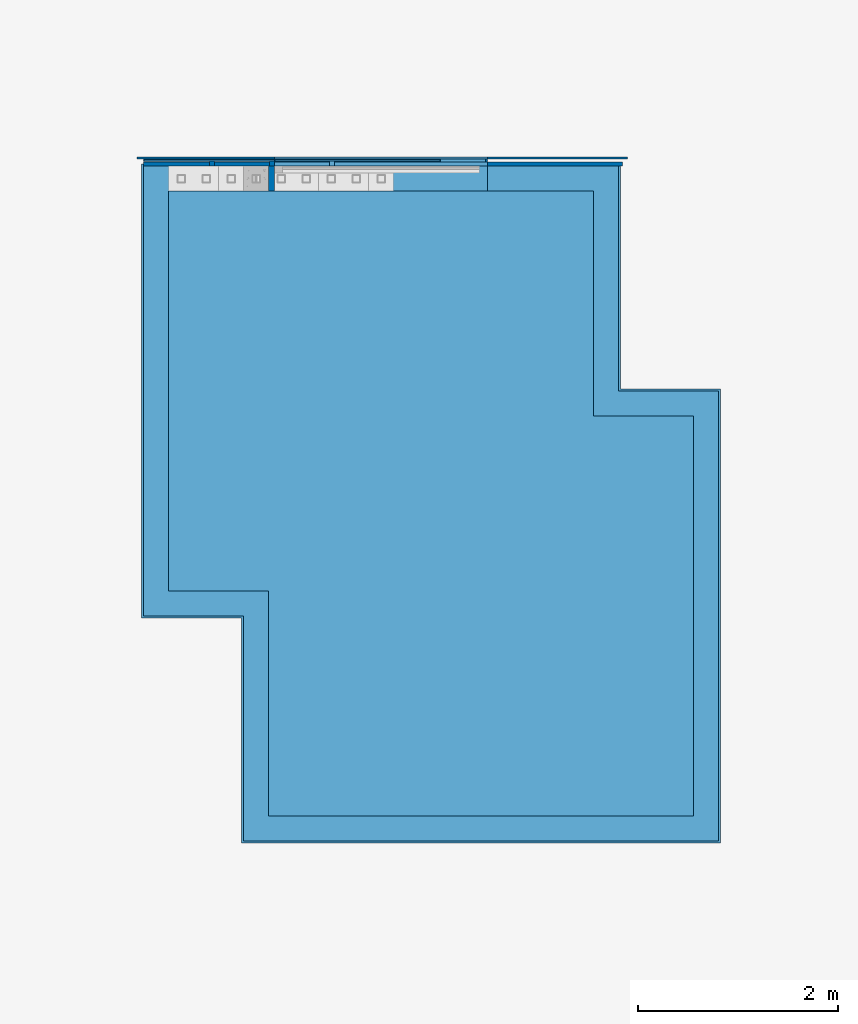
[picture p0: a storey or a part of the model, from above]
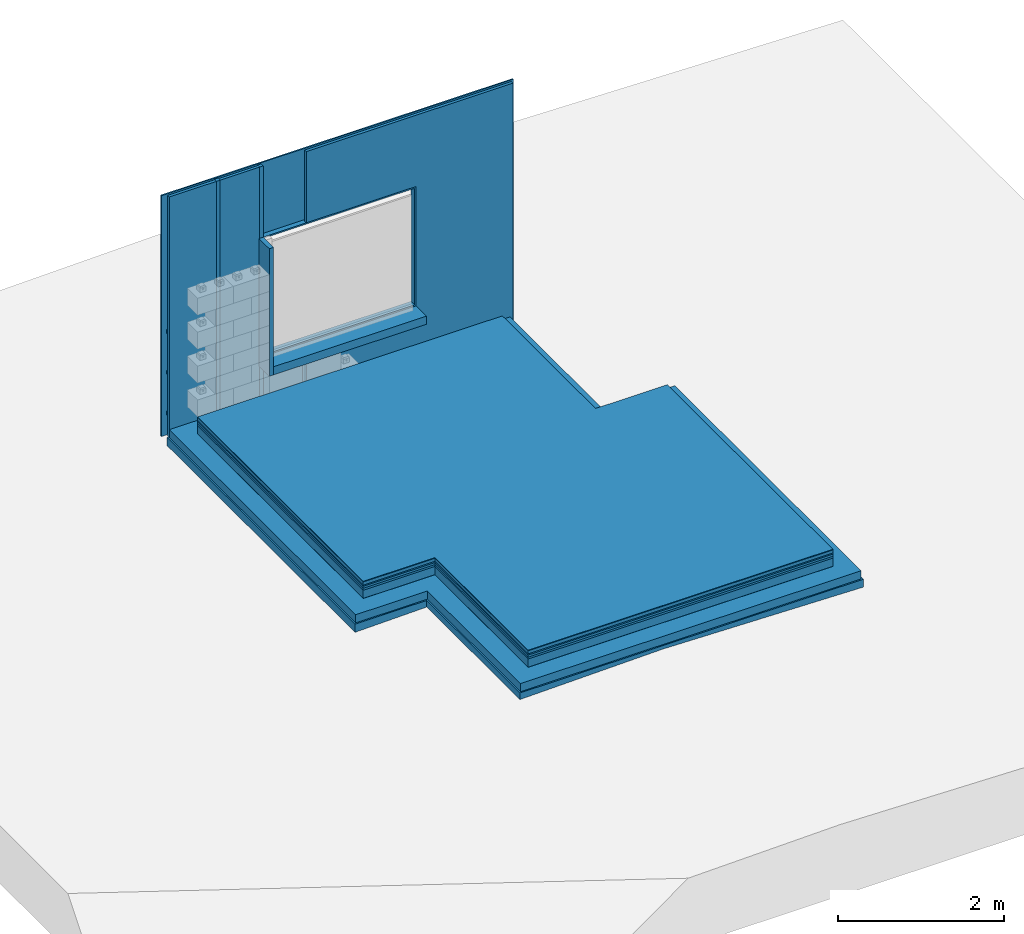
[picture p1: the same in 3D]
Properties of the parts of a building model (IFC4)

# File
Description: ViewDefinition [ReferenceView_V1.2], RevitIdentifiers [ContentGUID: 220a4939-3971-4e9b-89b3-fe80d098a815, VersionGUID: d7252125-2e6f-444e-b0fa-fdf360d79000, NumberOfSaves: 84], CoordinateReference [CoordinateBase: Internal Origin, ProjectSite: Internal], ExchangeRequirement [Architecture]
File name: 3dv__Detail__15__218, WS25.ifc
Time: 2025-12-19T14:07:46+01:00
Written by: ODA SDAI 25.12
Made in: Autodesk - Revit 26.3.0.37 (ENU) - 26.4.1.0

# IfcSite, Default
RefLatitude: 50, 59, 55, 811462; RefLongitude: 6, 47, 53, 300743; RefElevation: 0 cm

# IfcBuildingStorey (2)
Name | LongName | Elevation (cm)
L00__ABOVE Slab | L00__ABOVE Slab | -23.7
L01__ABOVE Slab | L01__ABOVE Slab | 269.3

# IfcBuildingElementPart (10)
In: L00__ABOVE Slab
Name | Material
2 x _FND LAYERS__Insulation__Foam Glass__Glapor PG UMB1 | _FND LAYERS__Insulation__Foam Glass__Glapor PG UMB1
_FLR LAYERS__Equalization Infill__Gravel | _FLR LAYERS__Equalization Infill__Gravel
_FLR LAYERS__Fleece__Glapor Connect | _FLR LAYERS__Fleece__Glapor Connect
_FLR LAYERS__Insulation__Wood-fiber__Gutex Standard N | _FLR LAYERS__Insulation__Wood-fiber__Gutex Standard N
_FLR LAYERS__Insulation__Wood-fiber__Gutex Thermosafe WD | _FLR LAYERS__Insulation__Wood-fiber__Gutex Thermosafe WD
_SL ROOF LAYERS__Decking Board__OSB 3 | _SL ROOF LAYERS__Decking Board__OSB 3
_FLR COVERING__Carpet Tiles__Tarkett | _FLR COVERING__Carpet Tiles__Tarkett
_FLR LAYERS__Fundaplan | _FLR LAYERS__Fundaplan
_FLR LAYERS__Screed__Dry__Litotherm LW86 | _FLR LAYERS__Screed__Dry__Litotherm LW86

# IfcGeographicElement: Toposolid : Toposolid : Toposolid 1
In: L00__ABOVE Slab
Type - PredefinedType: TERRAIN; Material: _STRUCTURE__Precast Concrete__Waterproof, _GREENERY__Subgrade__Earth

# IfcOpeningElement (2)
In: L00__ABOVE Slab
PredefinedType: OPENING

# IfcSlab: Floors : Floor : flr__INT COVERING__5.5cm__TriqBriq, FL.2
In: L00__ABOVE Slab
Type - PredefinedType: FLOOR
Classification: A 8.1.5 Floors on a dry screed base (Uniformat)

# IfcSlab: Floors : Floor : flr__INT COVERING__Wood Insulation, Decking Board 7.6cm__TriqBriq, FL.1
In: L00__ABOVE Slab
Type - PredefinedType: FLOOR
Classification: A 8.1 INTERNAL FLOORS (Uniformat)

# IfcSlab: Floors : Floor : flr__WP & INSULATION__12cm__TriqBriq, IZ.1
In: L00__ABOVE Slab
Type - PredefinedType: FLOOR
Classification: A 2.1.2 Thermal insulation and waterproofing - horizontal foundation surfaces (Uniformat)

# IfcSlab: Floors : Floor : flr__WP & INSULATION__Foam Glass 12.2cm__Under Bsmt Slab, TriqBriq, IZ.2
In: L00__ABOVE Slab
Type - PredefinedType: FLOOR
Classification: A 2.1.2 Thermal insulation and waterproofing - horizontal foundation surfaces (Uniformat)

# IfcSlab: Floors : Floor : flr__WP & INSULATION__Foam Glass 12cm__Under Bsmt Slab, TriqBriq, IZ.3
In: L00__ABOVE Slab
Type - PredefinedType: FLOOR
Classification: A 2.1.2 Thermal insulation and waterproofing - horizontal foundation surfaces (Uniformat)

# IfcWall (12)
In: L00__ABOVE Slab
Name (Parts :...) | Material
7 x  Part | _STRUCTURE__Wood Solid
4 x  Part | _FCD LAYERS__Insulation__Wood-fiber__Gutex Multitherm
 Part | _FCD VENT FINISH__Wood__Thermory C34

# IfcWall: Columns : wll_s__TIMBER BLOCK__Triqbriq, Full Width__wp : WS25 (17)
In: L00__ABOVE Slab
Type - PredefinedType: SOLIDWALL; Material: Miscellaneous__Timber Block__Triqbriq, Y
Classification: A 1.0.1 Load-bearing modular timber frame construction (Uniformat)

# IfcWall: Columns : wll_s__TIMBER BLOCK__Triqbriq, Half Width__wp : WS25 (3)
In: L00__ABOVE Slab
Type - PredefinedType: SOLIDWALL; Material: Miscellaneous__Timber Block__Triqbriq, Y
Classification: A 1.0.1 Load-bearing modular timber frame construction (Uniformat)

# IfcWall: Structural Framing : wll_s__LINTEL__Triqbriq, Rectangular__wp : Wood (2)
In: L00__ABOVE Slab
Type - PredefinedType: SOLIDWALL; Material: _STRUCTURE__Wood Solid
Classification: A 1.0.3 Modular Wood Frame Wall Add-on Components (Uniformat)

# IfcWindow: Windows : wdw_s__PANEL__Fixed__wp : Glazed
In: L00__ABOVE Slab
Type - PredefinedType: WINDOW; Material: _WINDOW__Glazing
OverallHeight: 7 cm; OverallWidth: 197 cm

# IfcWindow: Windows : wdw_s__PROFILE__Frame__wp : Wood (2)
In: L00__ABOVE Slab
Type - PredefinedType: WINDOW; Material: _WINDOW__Profile__Wood
OverallHeight: 28.3557 cm; OverallWidth: 8 cm
